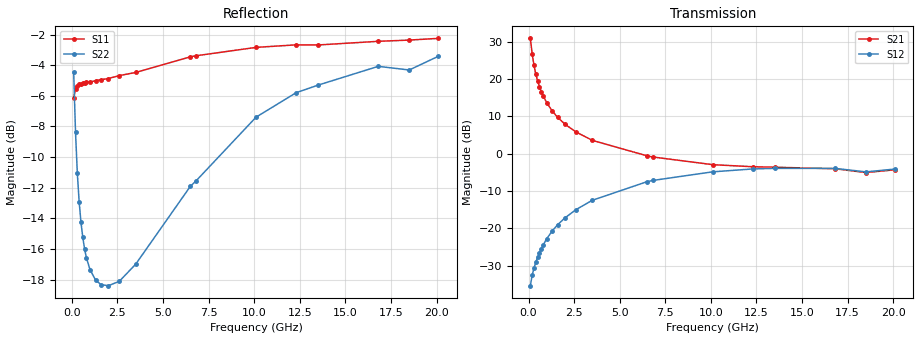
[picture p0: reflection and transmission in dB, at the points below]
!  Infineon Technologies AG
! BFR380L3 , PF131585-7, No.6, Th 09.10.01, soldered on pcb-board, measured with PP GSG850
!  Vce=5.0 V,  Ic=80.0 mA
! Common Emitter S-Parameters:  15. November 2001
#  GHz  S  MA  R  50
! f  S11  S21  S12  S22
! GHz  Mag  Ang  Mag  Ang  Mag  Ang  Mag  Ang
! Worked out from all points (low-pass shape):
!   201 points, 100 MHz to 20.1 GHz, reference 50 ohm
!   highest |S21| = 30.86 dB at 100 MHz (marker M1); lowest = -5.0 dB at 18.5 GHz (marker M2)
!   |S21| within 3 dB of the highest: start of sweep to 171.5 MHz
!   lowest |S11| = -6.1 dB at 100 MHz (marker M3), VSWR 2.95, Z = 25.9 - j33 ohm
!   |S11| at or under -10 dB: nowhere
!   |S22| runs from -18.4 to -3.4 dB; largest |S21 - S12| = 35
!   S11 on the Smith chart (normalised r, x): 100 MHz: 0.52, -0.66; 400 MHz: 0.30, -0.15; 2.6 GHz: 0.28, +0.27; 6.5 GHz: 0.32, +0.76; 12.3 GHz: 0.53, +1.52; 20.1 GHz: 1.11, +2.55
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0.1  0.4933 -102.7  34.92 131.8  0.01718 58.4  0.599 -42.3
0.2  0.5278 -137.3  21.54 112.1  0.02369 56.3  0.3818 -56.3
0.3  0.5403 -153.0  15.17 102.9  0.02964 58.5  0.2804 -60.5
0.4  0.5469 -161.7  11.62 97.2  0.03529 61.2  0.226 -61.9
0.5  0.5487 -167.7  9.396 93.1  0.04132 63.9  0.1937 -62.4
0.6  0.5501 -172.4  7.881 89.9  0.0475 65.5  0.173 -62.5
0.7  0.5532 -176.2  6.792 87.1  0.05371 67.0  0.1583 -62.8
0.8  0.5546 -179.2  5.964 84.5  0.06004 68.1  0.1482 -63.3
1  0.5568 175.5  4.805 80.2  0.07307 69.3  0.1355 -64.9
1.3  0.5613 169.0  3.73 74.4  0.09274 69.7  0.1255 -69.0
1.6  0.5659 163.4  3.062 69.2  0.1126 69.5  0.1212 -74.4
2  0.5708 156.8  2.482 62.7  0.1388 68.2  0.1203 -82.8
2.6  0.5836 147.6  1.955 53.8  0.1786 65.5  0.1243 -97.4
3.5  0.5975 135.0  1.509 41.7  0.2385 60.3  0.1414 -117.8
6.5  0.672 101.7  0.9374 11.7  0.4229 39.7  0.254 -178.4
6.8  0.6773 98.7  0.9055 9.5  0.4387 37.2  0.2641 176.7
10.1  0.7215 73.9  0.7141 -8.1  0.5727 13.8  0.427 135.2
12.3  0.7354 62.4  0.6699 -16.4  0.6261 -0.9  0.5133 112.6
13.5  0.7347 56.8  0.6602 -21.2  0.6369 -8.4  0.5433 102.8
16.8  0.7551 45.9  0.6295 -31.5  0.637 -24.9  0.6256 79.4
18.5  0.7622 43.9  0.5599 -38.8  0.5717 -33.1  0.6088 73.4
20.1  0.7721 37.1  0.6102 -42.6  0.6241 -38.6  0.6751 62.2
